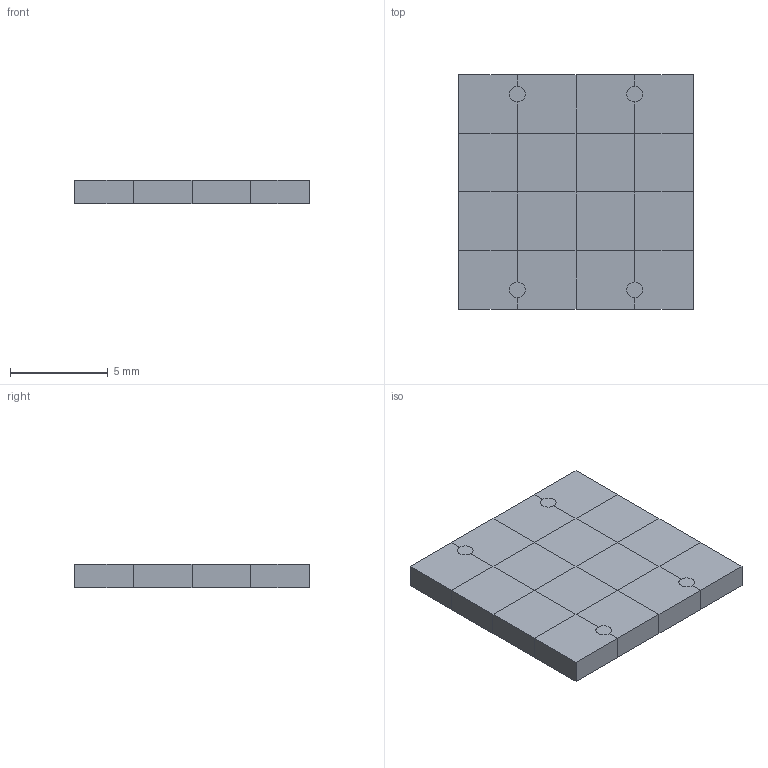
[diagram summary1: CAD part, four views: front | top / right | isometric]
STEP (ISO 10303-21) file: header records copied from the file, then geometry measured from it (millimetres).
FILE_DESCRIPTION(('Open CASCADE Model'),'2;1');
FILE_NAME('Open CASCADE Shape Model','2026-11-24T13:27:00',('Author'),( 'Open CASCADE'),'Open CASCADE STEP processor 7.9','Open CASCADE 7.9' ,'Unknown');
FILE_SCHEMA(('AUTOMOTIVE_DESIGN { 1 0 10303 214 1 1 1 1 }'));
Length unit declared in the file: millimetre
Products named in the file (3): manifold_design; fluid; solid
Assembly tree (2 placements, depth 2):
  manifold_design
    fluid
    solid
Bounding box: 12 x 12 x 1.2 mm (x, y, z)
Volume: 172.8 mm3; surface area: 1518.9 mm2
Topology: 2 solids, 2 shells, 1600 faces, 5904 edges, 3202 vertices
Faces by surface type: plane 1592, cylinder 8
Full cylindrical faces by diameter (mm): 0.8 x8
Entity records: 137518 total; most frequent: CARTESIAN_POINT 22565, DIRECTION 20934, LINE 17664, VECTOR 17664, ORIENTED_EDGE 11808, PCURVE 11808, DEFINITIONAL_REPRESENTATION 11808, EDGE_CURVE 5904
One B-rep face of a CAD part: STEP entity #73782.
In plain terms, the planar face has unit normal (0, 0, 1).
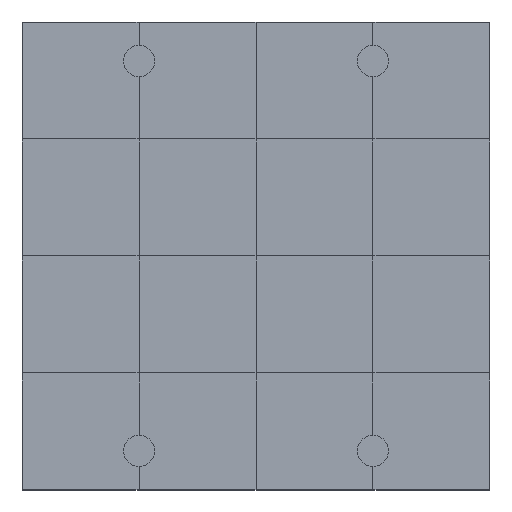
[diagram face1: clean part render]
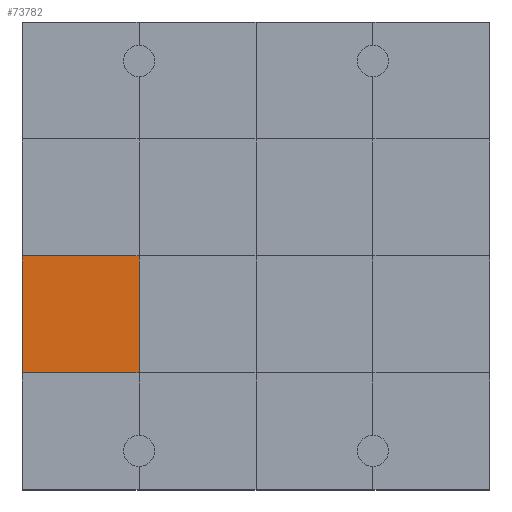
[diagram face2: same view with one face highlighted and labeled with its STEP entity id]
Its self-contained STEP definition (entity closure, numbers rounded to 3 decimals):
#73332 = VERTEX_POINT('',#73333);
#73333 = CARTESIAN_POINT('',(0.,3.,1.2));
#73347 = PLANE('',#73348);
#73348 = AXIS2_PLACEMENT_3D('',#73349,#73350,#73351);
#73349 = CARTESIAN_POINT('',(0.,3.,0.));
#73350 = DIRECTION('',(1.,0.,-0.));
#73351 = DIRECTION('',(0.,0.,1.));
#73373 = PLANE('',#73374);
#73374 = AXIS2_PLACEMENT_3D('',#73375,#73376,#73377);
#73375 = CARTESIAN_POINT('',(0.,0.,1.2));
#73376 = DIRECTION('',(0.,0.,1.));
#73377 = DIRECTION('',(1.,0.,-0.));
#73524 = VERTEX_POINT('',#73525);
#73525 = CARTESIAN_POINT('',(3.,3.,1.2));
#73546 = EDGE_CURVE('',#73332,#73524,#73547,.T.);
#73547 = SURFACE_CURVE('',#73548,(#73552,#73559),.PCURVE_S1.);
#73548 = LINE('',#73549,#73550);
#73549 = CARTESIAN_POINT('',(0.,3.,1.2));
#73550 = VECTOR('',#73551,1.);
#73551 = DIRECTION('',(1.,0.,-0.));
#73552 = PCURVE('',#73373,#73553);
#73553 = DEFINITIONAL_REPRESENTATION('',(#73554),#73558);
#73554 = LINE('',#73555,#73556);
#73555 = CARTESIAN_POINT('',(0.,3.));
#73556 = VECTOR('',#73557,1.);
#73557 = DIRECTION('',(1.,0.));
#73558 = ( GEOMETRIC_REPRESENTATION_CONTEXT(2) 
PARAMETRIC_REPRESENTATION_CONTEXT() REPRESENTATION_CONTEXT('2D SPACE',''
  ) );
#73559 = PCURVE('',#73560,#73565);
#73560 = PLANE('',#73561);
#73561 = AXIS2_PLACEMENT_3D('',#73562,#73563,#73564);
#73562 = CARTESIAN_POINT('',(0.,3.,1.2));
#73563 = DIRECTION('',(0.,0.,1.));
#73564 = DIRECTION('',(1.,0.,-0.));
#73565 = DEFINITIONAL_REPRESENTATION('',(#73566),#73570);
#73566 = LINE('',#73567,#73568);
#73567 = CARTESIAN_POINT('',(0.,0.));
#73568 = VECTOR('',#73569,1.);
#73569 = DIRECTION('',(1.,0.));
#73570 = ( GEOMETRIC_REPRESENTATION_CONTEXT(2) 
PARAMETRIC_REPRESENTATION_CONTEXT() REPRESENTATION_CONTEXT('2D SPACE',''
  ) );
#73605 = VERTEX_POINT('',#73606);
#73606 = CARTESIAN_POINT('',(0.,6.,1.2));
#73632 = EDGE_CURVE('',#73332,#73605,#73633,.T.);
#73633 = SURFACE_CURVE('',#73634,(#73638,#73645),.PCURVE_S1.);
#73634 = LINE('',#73635,#73636);
#73635 = CARTESIAN_POINT('',(0.,3.,1.2));
#73636 = VECTOR('',#73637,1.);
#73637 = DIRECTION('',(-0.,1.,0.));
#73638 = PCURVE('',#73347,#73639);
#73639 = DEFINITIONAL_REPRESENTATION('',(#73640),#73644);
#73640 = LINE('',#73641,#73642);
#73641 = CARTESIAN_POINT('',(1.2,0.));
#73642 = VECTOR('',#73643,1.);
#73643 = DIRECTION('',(0.,-1.));
#73644 = ( GEOMETRIC_REPRESENTATION_CONTEXT(2) 
PARAMETRIC_REPRESENTATION_CONTEXT() REPRESENTATION_CONTEXT('2D SPACE',''
  ) );
#73645 = PCURVE('',#73560,#73646);
#73646 = DEFINITIONAL_REPRESENTATION('',(#73647),#73651);
#73647 = LINE('',#73648,#73649);
#73648 = CARTESIAN_POINT('',(0.,0.));
#73649 = VECTOR('',#73650,1.);
#73650 = DIRECTION('',(0.,1.));
#73651 = ( GEOMETRIC_REPRESENTATION_CONTEXT(2) 
PARAMETRIC_REPRESENTATION_CONTEXT() REPRESENTATION_CONTEXT('2D SPACE',''
  ) );
#73782 = ADVANCED_FACE('',(#73783),#73560,.T.);
#73783 = FACE_BOUND('',#73784,.T.);
#73784 = EDGE_LOOP('',(#73785,#73786,#73787,#73815));
#73785 = ORIENTED_EDGE('',*,*,#73632,.F.);
#73786 = ORIENTED_EDGE('',*,*,#73546,.T.);
#73787 = ORIENTED_EDGE('',*,*,#73788,.T.);
#73788 = EDGE_CURVE('',#73524,#73789,#73791,.T.);
#73789 = VERTEX_POINT('',#73790);
#73790 = CARTESIAN_POINT('',(3.,6.,1.2));
#73791 = SURFACE_CURVE('',#73792,(#73796,#73803),.PCURVE_S1.);
#73792 = LINE('',#73793,#73794);
#73793 = CARTESIAN_POINT('',(3.,3.,1.2));
#73794 = VECTOR('',#73795,1.);
#73795 = DIRECTION('',(-0.,1.,0.));
#73796 = PCURVE('',#73560,#73797);
#73797 = DEFINITIONAL_REPRESENTATION('',(#73798),#73802);
#73798 = LINE('',#73799,#73800);
#73799 = CARTESIAN_POINT('',(3.,0.));
#73800 = VECTOR('',#73801,1.);
#73801 = DIRECTION('',(0.,1.));
#73802 = ( GEOMETRIC_REPRESENTATION_CONTEXT(2) 
PARAMETRIC_REPRESENTATION_CONTEXT() REPRESENTATION_CONTEXT('2D SPACE',''
  ) );
#73803 = PCURVE('',#73804,#73809);
#73804 = PLANE('',#73805);
#73805 = AXIS2_PLACEMENT_3D('',#73806,#73807,#73808);
#73806 = CARTESIAN_POINT('',(3.,3.,1.2));
#73807 = DIRECTION('',(0.,0.,1.));
#73808 = DIRECTION('',(1.,0.,-0.));
#73809 = DEFINITIONAL_REPRESENTATION('',(#73810),#73814);
#73810 = LINE('',#73811,#73812);
#73811 = CARTESIAN_POINT('',(0.,0.));
#73812 = VECTOR('',#73813,1.);
#73813 = DIRECTION('',(0.,1.));
#73814 = ( GEOMETRIC_REPRESENTATION_CONTEXT(2) 
PARAMETRIC_REPRESENTATION_CONTEXT() REPRESENTATION_CONTEXT('2D SPACE',''
  ) );
#73815 = ORIENTED_EDGE('',*,*,#73816,.F.);
#73816 = EDGE_CURVE('',#73605,#73789,#73817,.T.);
#73817 = SURFACE_CURVE('',#73818,(#73822,#73829),.PCURVE_S1.);
#73818 = LINE('',#73819,#73820);
#73819 = CARTESIAN_POINT('',(0.,6.,1.2));
#73820 = VECTOR('',#73821,1.);
#73821 = DIRECTION('',(1.,0.,-0.));
#73822 = PCURVE('',#73560,#73823);
#73823 = DEFINITIONAL_REPRESENTATION('',(#73824),#73828);
#73824 = LINE('',#73825,#73826);
#73825 = CARTESIAN_POINT('',(0.,3.));
#73826 = VECTOR('',#73827,1.);
#73827 = DIRECTION('',(1.,0.));
#73828 = ( GEOMETRIC_REPRESENTATION_CONTEXT(2) 
PARAMETRIC_REPRESENTATION_CONTEXT() REPRESENTATION_CONTEXT('2D SPACE',''
  ) );
#73829 = PCURVE('',#73830,#73835);
#73830 = PLANE('',#73831);
#73831 = AXIS2_PLACEMENT_3D('',#73832,#73833,#73834);
#73832 = CARTESIAN_POINT('',(0.,6.,1.2));
#73833 = DIRECTION('',(0.,0.,1.));
#73834 = DIRECTION('',(1.,0.,-0.));
#73835 = DEFINITIONAL_REPRESENTATION('',(#73836),#73840);
#73836 = LINE('',#73837,#73838);
#73837 = CARTESIAN_POINT('',(0.,0.));
#73838 = VECTOR('',#73839,1.);
#73839 = DIRECTION('',(1.,0.));
#73840 = ( GEOMETRIC_REPRESENTATION_CONTEXT(2) 
PARAMETRIC_REPRESENTATION_CONTEXT() REPRESENTATION_CONTEXT('2D SPACE',''
  ) );
